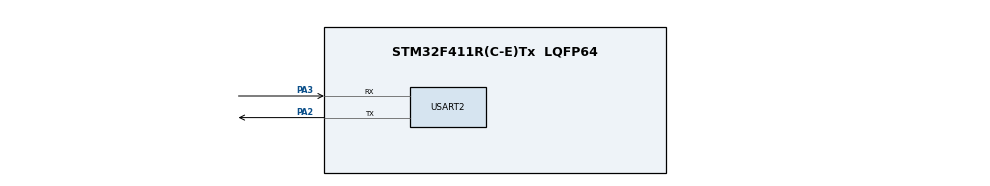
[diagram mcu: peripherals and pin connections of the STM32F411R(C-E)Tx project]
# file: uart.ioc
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Mcu.Family=STM32F4
Mcu.Name=STM32F411R(C-E)Tx
Mcu.Package=LQFP64
NVIC.PriorityGroup=NVIC_PRIORITYGROUP_4
NVIC.USART2_IRQn=true\:0\:0\:false\:false\:true\:true\:true\:true
PA13.Mode=Serial_Wire
PA13.Signal=SYS_JTMS-SWDIO
PA14.Mode=Serial_Wire
PA14.Signal=SYS_JTCK-SWCLK
PA2.Mode=Asynchronous
PA2.Signal=USART2_TX
PA3.Mode=Asynchronous
PA3.Signal=USART2_RX
ProjectManager.HeapSize=0x200
ProjectManager.StackSize=0x400
ProjectManager.TargetToolchain=STM32CubeIDE
RCC.48MHZClocksFreq_Value=32000000
RCC.AHBFreq_Value=64000000
RCC.APB1CLKDivider=RCC_HCLK_DIV2
RCC.APB1Freq_Value=32000000
RCC.APB1TimFreq_Value=64000000
RCC.APB2Freq_Value=64000000
RCC.APB2TimFreq_Value=64000000
RCC.CortexFreq_Value=64000000
RCC.HCLKFreq_Value=64000000
RCC.HSE_VALUE=25000000
RCC.HSI_VALUE=16000000
RCC.LSE_VALUE=32768
RCC.PLLM=8
RCC.PLLN=64
RCC.SYSCLKFreq_VALUE=64000000
RCC.SYSCLKSource=RCC_SYSCLKSOURCE_PLLCLK
RCC.VCOOutputFreq_Value=128000000
USART2.VirtualMode=VM_ASYNC
board=custom

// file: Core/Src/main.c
/* USER CODE BEGIN Header */
/**
 ******************************************************************************
 * @file           : main.c
 * @brief          : Main program body
 ******************************************************************************
 * @attention
 *
 * Copyright (c) 2024 STMicroelectronics.
 * All rights reserved.
 *
 * This software is licensed under terms that can be found in the LICENSE file
 * in the root directory of this software component.
 * If no LICENSE file comes with this software, it is provided AS-IS.
 *
 ******************************************************************************
 */
/* USER CODE END Header */
#include "main.h"

/* USER CODE BEGIN Includes */
#include <stdbool.h>
#include <stdio.h>
#include <string.h>
#include <math.h>
#include "uart.h"
/* USER CODE END Includes */

UART_HandleTypeDef huart2;

void SystemClock_Config(void);
static void MX_GPIO_Init(void);
static void MX_USART2_UART_Init(void);

int main(void) {

	/* MCU Configuration--------------------------------------------------------*/

	/* Reset of all peripherals, Initializes the Flash interface and the Systick. */
	HAL_Init();

	/* Configure the system clock */
	SystemClock_Config();

	/* Initialize all configured peripherals */
	MX_GPIO_Init();
	MX_USART2_UART_Init();
	/* USER CODE BEGIN 2 */
	initUART(&huart2);
	/* USER CODE END 2 */

	/* Infinite loop */
	while (1) {
		static int angle = 0;
		static bool flagState = false;
		uint8_t ch;

		ch = getChar();
		if (ch == 'S') {
			uint8_t strValue[6] = {0, };
			strValue[0] = 'S';

			for (int i = 1; i < 6; i++) {
				ch = getChar();
				strValue[i] = ch;
			}
			if ((strncmp(strValue, "START", 5) == 0) && (strlen(strValue)==5))  {
				flagState = true;
			}
			if ((strncmp(strValue, "STOP", 4) == 0) && (strlen(strValue)==4)){
				flagState = false;
			}
		}

		int32_t data[10]; //signed integer 32bit (-2^16 ~ 2^16)
		angle++;
		angle %= 360;
		for (int i = 0; i < 10; i++) {
			data[i] = sin((angle + i * 36) * 3.14 / 180) * 10000;
		}

		// data[] = {0, 1736, 3462, 5000, 5000, 3462, 1736, 0, -1736, - 3462}
		// 32bit * 10 => 320bit = 40byte

		uint8_t txBuffer[42];
		txBuffer[0] = 0xaa;
		txBuffer[1] = 0xbb;
		memcpy(&txBuffer[2], data, 40); //8bit standard
		if (flagState)
			HAL_UART_Transmit(&huart2, txBuffer, 42, 10);
		HAL_Delay(1);
	}
}

void SystemClock_Config(void) {
	RCC_OscInitTypeDef RCC_OscInitStruct = { 0 };
	RCC_ClkInitTypeDef RCC_ClkInitStruct = { 0 };

	/** Configure the main internal regulator output voltage
	 */
	__HAL_RCC_PWR_CLK_ENABLE();
	__HAL_PWR_VOLTAGESCALING_CONFIG(PWR_REGULATOR_VOLTAGE_SCALE1);

	/** Initializes the RCC Oscillators according to the specified parameters
	 * in the RCC_OscInitTypeDef structure.
	 */
	RCC_OscInitStruct.OscillatorType = RCC_OSCILLATORTYPE_HSI;
	RCC_OscInitStruct.HSIState = RCC_HSI_ON;
	RCC_OscInitStruct.HSICalibrationValue = RCC_HSICALIBRATION_DEFAULT;
	RCC_OscInitStruct.PLL.PLLState = RCC_PLL_NONE;
	if (HAL_RCC_OscConfig(&RCC_OscInitStruct) != HAL_OK) {
		Error_Handler();
	}

	/** Initializes the CPU, AHB and APB buses clocks
	 */
	RCC_ClkInitStruct.ClockType = RCC_CLOCKTYPE_HCLK | RCC_CLOCKTYPE_SYSCLK
			| RCC_CLOCKTYPE_PCLK1 | RCC_CLOCKTYPE_PCLK2;
	RCC_ClkInitStruct.SYSCLKSource = RCC_SYSCLKSOURCE_HSI;
	RCC_ClkInitStruct.AHBCLKDivider = RCC_SYSCLK_DIV1;
	RCC_ClkInitStruct.APB1CLKDivider = RCC_HCLK_DIV1;
	RCC_ClkInitStruct.APB2CLKDivider = RCC_HCLK_DIV1;

	if (HAL_RCC_ClockConfig(&RCC_ClkInitStruct, FLASH_LATENCY_0) != HAL_OK) {
		Error_Handler();
	}
}

static void MX_USART2_UART_Init(void) {

	huart2.Instance = USART2;
	huart2.Init.BaudRate = 115200;
	huart2.Init.WordLength = UART_WORDLENGTH_8B;
	huart2.Init.StopBits = UART_STOPBITS_1;
	huart2.Init.Parity = UART_PARITY_NONE;
	huart2.Init.Mode = UART_MODE_TX_RX;
	huart2.Init.HwFlowCtl = UART_HWCONTROL_NONE;
	huart2.Init.OverSampling = UART_OVERSAMPLING_16;
	if (HAL_UART_Init(&huart2) != HAL_OK) {
		Error_Handler();
	}

}

static void MX_GPIO_Init(void) {

	/* GPIO Ports Clock Enable */
	__HAL_RCC_GPIOA_CLK_ENABLE();

}

void Error_Handler(void) {
	__disable_irq();
	while (1) {
	}
}
